! (c) 2009  Infineon Technologies AG, Munich
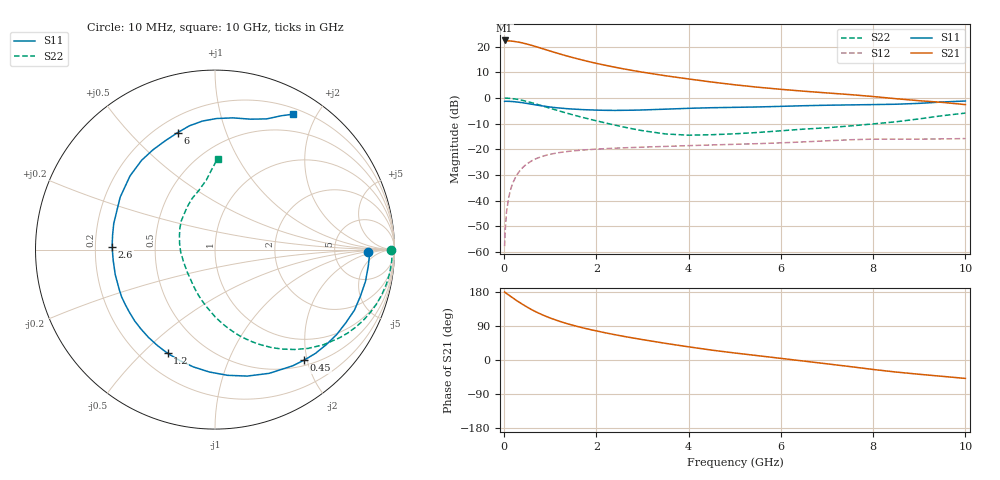
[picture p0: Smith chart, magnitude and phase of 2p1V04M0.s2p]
! Infineon Technologies  Discrete & RF Semiconductors
! BFP420
! VCE =  1.0 V,  IC =  4.0 mA
! Common Emitter S-Parameters:  Nov 2009
# GHz  S  MA  R  50
!  f  S11  S21  S12  S22
! GHz  MAG  ANG  MAG  ANG  MAG  ANG  MAG  ANG
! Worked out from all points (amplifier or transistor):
!   46 points, 10 MHz to 10 GHz, reference 50 ohm
!   highest |S21| = 22.4 dB at 10 MHz (marker M1)
!   |S21| within 3 dB of that: start of sweep to 795.7 MHz
!   unconditionally stable (mu >= 1): 3.212 GHz to end of sweep
!   at 300 MHz: K = 0.09, MSG = 25.5 dB, |S12| = -29.3 dB
!   at 1.7 GHz: K = 0.54, MSG = 17.5 dB, |S12| = -20.3 dB
!   at 10 GHz: K = 1.13, MAG = 4.4 dB, |S12| = -15.8 dB
!   lowest NFmin = 0.61 dB at 900 MHz
!   S11 on the Smith chart (normalised r, x): 10 MHz: 13, -1; 450 MHz: 0.59, -1.95; 1.2 GHz: 0.31, -0.60; 2.6 GHz: 0.27, +0.01; 6 GHz: 0.28, +0.69; 10 GHz: 0.27, +1.70
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0.01  0.8543 -0.9  13.12 179.3  0.0013 98.0  0.9831 0.0
0.02  0.861 -2.4  12.79 178.6  0.0023 83.0  0.9878 -1.5
0.05  0.8591 -5.9  12.84 175.7  0.0059 87.3  0.9864 -3.8
0.1  0.857 -11.9  12.87 171.4  0.0117 83.9  0.9823 -7.6
0.25  0.8352 -29.2  12.41 158.5  0.0289 74.4  0.9494 -18.7
0.35  0.8154 -40.4  11.99 150.7  0.0392 68.3  0.914 -25.8
0.45  0.7911 -51.1  11.43 143.1  0.0483 62.8  0.8724 -32.3
0.6  0.7527 -66.3  10.51 132.6  0.0598 55.5  0.8034 -41.3
0.7  0.7272 -75.7  9.887 126.4  0.0661 51.1  0.7564 -46.7
0.9  0.6828 -92.6  8.694 115.5  0.076 44.0  0.6677 -56.1
1.2  0.6353 -114.6  7.199 102.1  0.0863 35.8  0.5542 -68.0
1.4  0.6137 -127.1  6.399 94.7  0.0911 31.7  0.4929 -74.8
1.7  0.5915 -143.4  5.447 85.1  0.0965 26.8  0.4175 -83.9
2.2  0.573 -165.9  4.304 71.6  0.103 20.7  0.3251 -97.8
2.6  0.5737 178.4  3.659 62.2  0.1068 16.9  0.2701 -110.0
3.5  0.6036 151.1  2.696 43.9  0.1137 10.7  0.1988 -141.1
4.5  0.6441 129.4  2.037 26.1  0.1213 5.2  0.192 -176.6
5.5  0.6664 114.7  1.614 11.4  0.1286 0.8  0.2123 159.0
6  0.6842 107.7  1.469 4.3  0.1333 -1.3  0.229 148.7
7  0.7197 95.5  1.249 -10.1  0.1462 -6.8  0.2623 131.0
8.5  0.753 74.8  0.963 -31.8  0.1576 -19.4  0.3431 105.0
10  0.87 60.1  0.74 -48.6  0.1615 -27.3  0.5062 88.4
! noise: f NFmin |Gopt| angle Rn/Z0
0.9  0.61  0.27  32  0.16
1.8  1.03  0.14  83  0.13
2.4  1.11  0.17  110  0.14
3  1.23  0.2  153  0.11
4  1.42  0.31  -151  0.11
5  1.77  0.38  -123  0.23
6  2.35  0.47  -104  0.33
